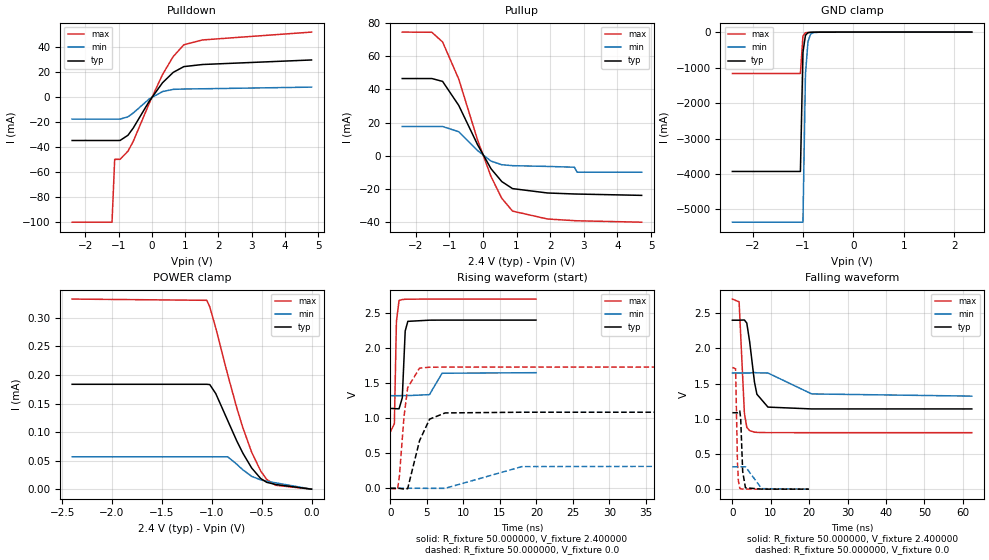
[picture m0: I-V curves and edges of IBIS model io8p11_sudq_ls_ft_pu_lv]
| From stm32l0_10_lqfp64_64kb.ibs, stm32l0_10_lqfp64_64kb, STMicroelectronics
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|   Model io8p11_sudq_ls_ft_pu_lv
[Model]  io8p11_sudq_ls_ft_pu_lv
Model_type I/O
Polarity   Non-Inverting
Enable   Active-Low
Vinl =   0.720000V
Vinh =   1.680000V
Vmeas =  1.200000V
Cref =   50.000000pF
Rref =   100.000000M
Vref =   0.0V
C_comp   2.317700pF   2.286600pF   2.332700pF
[Temperature Range]   25.000000   0.105000k   -40.000000
[Pullup Reference]   2.400000V   1.650000V   2.700000V
[Pulldown Reference]   0.0V   0.0V   0.0V
[POWER Clamp Reference]   2.400000V   1.650000V   2.700000V
[GND Clamp Reference]   0.0V   0.0V   0.0V
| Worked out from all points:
|   slope of the pulldown table from 0 to 0.36 V, typ, clamps not added: 28.4 ohm
|   slope of the pullup table from 0 to 0.36 V, typ, clamps not added: 32.2 ohm
|   GND clamp passes 1 mA (typ) near -0.65 V on its own axis
|   rising waveform, R_fixture 50.000000, V_fixture 2.400000: 20-80 % time 278ps typ, 636ps min, 186ps max; typ from 1.14 V to 2.4 V
|   rising waveform, R_fixture 50.000000, V_fixture 0.0: 20-80 % time 1.58ns typ, 3.85ns min, 917ps max; typ from 0.001 V to 1.09 V
|   falling waveform, R_fixture 50.000000, V_fixture 2.400000: 20-80 % time 1.8ns typ, 5.29ns min, 908ps max; typ from 2.4 V to 1.14 V
|   falling waveform, R_fixture 50.000000, V_fixture 0.0: 20-80 % time 464ps typ, 849ps min, 363ps max; typ from 1.09 V to 0.001 V
[Pulldown]
|Voltage   I(typ)   I(min)   I(max)
-2.4V     -34.71mA   -17.62mA   -100mA
-1.2V     -34.71mA   -17.62mA   -100mA
-1.12V    -34.71mA   -17.62mA   -49.77mA
-960mV    -34.71mA   -17.62mA   -49.77mA
-720mV    -30.52mA   -15.81mA   -43.24mA
-560mV    -24.66mA   -12.69mA   -35.31mA
-80mV     -3.3mA     -1.497mA   -4.982mA
320mV     11.47mA    4.39mA     18.08mA
640mV     19.72mA    6.139mA    32.34mA
960mV     24.33mA    6.432mA    41.77mA
1.52V     26.01mA    6.613mA    45.64mA
4.8V      29.64mA    7.944mA    51.92mA
[Pullup]
|Voltage   I(typ)   I(min)   I(max)
-2.4V     46.57mA    17.6mA     74.62mA
-1.52V    46.57mA    17.6mA     74.51mA
-1.2V     44.84mA    17.6mA     68.64mA
-720mV    30.34mA    14.43mA    46.24mA
-160mV    6.617mA    3.074mA    9.467mA
240mV     -7.917mA   -3.299mA   -12.65mA
560mV     -15.67mA   -5.497mA   -25.76mA
880mV     -19.92mA   -6.062mA   -33.51mA
1.92V     -22.56mA   -6.511mA   -38.27mA
2.72V     -23.16mA   -7mA       -39.27mA
2.8V      -23.2mA    -10mA      -39.35mA
4.72V     -24mA      -10mA      -40.2mA
[GND_clamp]
|Voltage   I(typ)   I(min)   I(max)
-2.4V     -3.929A    -5.359A    -1.166A
-1.05V    -3.929A    -5.359A    -1.166A
-1V       -574.5mA   -5.359A    -109.1mA
-950mV    -90.02mA   -1.192A    -18.55mA
-900mV    -18.41mA   -269.7mA   -9.049mA
-850mV    -6.764mA   -63.59mA   -6.579mA
-800mV    -4.027mA   -16.66mA   -4.859mA
-650mV    -1.043mA   -1.218mA   -1.146mA
2.35V     0A         0A         0A
[POWER_clamp]
|Voltage   I(typ)   I(min)   I(max)
-2.4V     183.7uA    56.67uA    333uA
-1.05V    183.7uA    56.67uA    330.8uA
-1.02V    183.2uA    56.67uA    319.3uA
-960mV    167.4uA    56.67uA    282.2uA
-840mV    120.1uA    56.67uA    200.3uA
-750mV    84.75uA    43.78uA    142.9uA
-690mV    63.55uA    34.11uA    108.5uA
-600mV    37.04uA    22.44uA    64.62uA
-510mV    18.73uA    16.34uA    31.91uA
-450mV    12.06uA    14.02uA    17.25uA
-360mV    8.154uA    11.11uA    6.782uA
0V        0A         0A         0A
[Ramp]
| variable   typ   min   max
dV/dt_r  0.65095/1.57423n   0.19036/3.84287n   1.03799/0.91323n
dV/dt_f  0.75624/1.80298n   0.19416/5.27079n   1.13751/0.90631n
R_load = 50.000000
[Rising Waveform]
R_fixture= 50.000000
V_fixture= 2.400000
V_fixture_min= 1.650000
V_fixture_max= 2.700000
|time   V(typ)   V(min)   V(max)
0s        1.14V      1.322V     803.1mV
560.6ps   1.139V     1.322V     921.3mV
840.8ps   1.136V     1.322V     2.38V
1.201ns   1.135V     1.322V     2.68V
1.642ns   1.291V     1.323V     2.693V
2.042ns   2.244V     1.323V     2.697V
2.402ns   2.382V     1.323V     2.698V
5.365ns   2.399V     1.337V     2.7V
7.087ns   2.4V       1.642V     2.7V
19.94ns   2.4V       1.65V      2.7V
[Rising Waveform]
R_fixture= 50.000000
V_fixture= 0.0
V_fixture_min= 0.0
V_fixture_max= 0.0
|time   V(typ)   V(min)   V(max)
0s        877.7uV    1.336mV    741.5uV
1.001ns   989.6uV    1.332mV    -11.31mV
1.251ns   156.8uV    1.329mV    178.8mV
1.877ns   -9.653mV   1.326mV    1.021V
2.377ns   -4.834mV   1.343mV    1.434V
4.004ns   680.3mV    1.416mV    1.715V
5.38ns    987.5mV    -171.1uV   1.728V
7.508ns   1.076V     541.8uV    1.73V
18.02ns   1.086V     310.4mV    1.73V
62.31ns   1.086V     318.6mV    1.73V
[Falling Waveform]
R_fixture= 50.000000
V_fixture= 2.400000
V_fixture_min= 1.650000
V_fixture_max= 2.700000
|time   V(typ)   V(min)   V(max)
0s        2.4V       1.65V      2.7V
1.752ns   2.4V       1.65V      2.66V
3.128ns   2.403V     1.65V      1.081V
3.754ns   2.359V     1.65V      878mV
4.505ns   2.091V     1.65V      830.9mV
5.756ns   1.52V      1.658V     810.2mV
6.381ns   1.349V     1.652V     806.9mV
9.259ns   1.166V     1.65V      803.4mV
20.65ns   1.14V      1.353V     803.1mV
62.31ns   1.14V      1.322V     803.1mV
[Falling Waveform]
R_fixture= 50.000000
V_fixture= 0.0
V_fixture_min= 0.0
V_fixture_max= 0.0
|time   V(typ)   V(min)   V(max)
0s        1.086V     318.6mV    1.73V
840.8ps   1.086V     318.6mV    1.709V
1.321ns   1.085V     318.6mV    394.6mV
1.562ns   1.09V      318.6mV    122mV
1.922ns   1.112V     318.6mV    15.91mV
2.162ns   1.008V     318.6mV    5.315mV
2.683ns   250.5mV    318.4mV    2.596mV
3.403ns   20.49mV    318.5mV    1.769mV
7.648ns   1.255mV    8.018mV    759uV
19.94ns   877.7uV    1.336mV    741.5uV
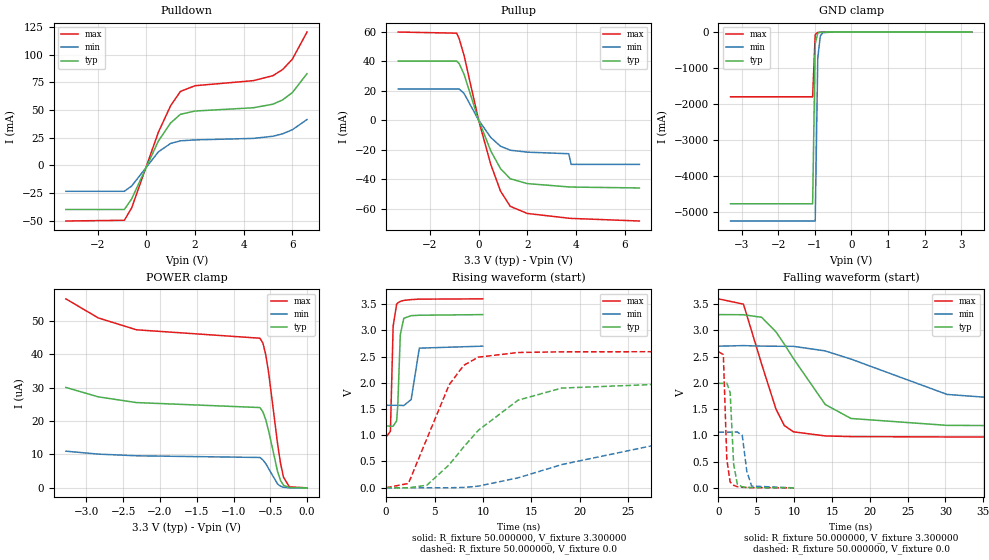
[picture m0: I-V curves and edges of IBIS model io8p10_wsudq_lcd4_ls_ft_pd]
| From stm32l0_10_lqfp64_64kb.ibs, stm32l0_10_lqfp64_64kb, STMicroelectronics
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|   Model io8p10_wsudq_lcd4_ls_ft_pd
[Model]  io8p10_wsudq_lcd4_ls_ft_pd
Model_type I/O
Polarity   Non-Inverting
Enable   Active-Low
Vinl =   0.990000V
Vinh =   2.310000V
Vmeas =  1.650000V
Cref =   50.000000pF
Rref =   100.000000M
Vref =   0.0V
C_comp   3.263700pF   3.224800pF   3.309000pF
[Temperature Range]   25.000000   0.125000k   -40.000000
[Pullup Reference]   3.300000V   2.700000V   3.600000V
[Pulldown Reference]   0.0V   0.0V   0.0V
[POWER Clamp Reference]   3.300000V   2.700000V   3.600000V
[GND Clamp Reference]   0.0V   0.0V   0.0V
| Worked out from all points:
|   slope of the pulldown table from 0 to 0.495 V, typ, clamps not added: 22.6 ohm
|   slope of the pullup table from 0 to 0.495 V, typ, clamps not added: 23.9 ohm
|   GND clamp passes 1 mA (typ) near -0.64 V on its own axis
|   rising waveform, R_fixture 50.000000, V_fixture 3.300000: 20-80 % time 236ps typ, 376ps min, 201ps max; typ from 1.18 V to 3.3 V
|   rising waveform, R_fixture 50.000000, V_fixture 0.0: 20-80 % time 6.53ns typ, 13.6ns min, 3.48ns max; typ from 0 V to 1.99 V
|   falling waveform, R_fixture 50.000000, V_fixture 3.300000: 20-80 % time 5.96ns typ, 12.5ns min, 3.27ns max; typ from 3.3 V to 1.18 V
|   falling waveform, R_fixture 50.000000, V_fixture 0.0: 20-80 % time 413ps typ, 576ps min, 337ps max; typ from 1.99 V to 0 V
[Pulldown]
|Voltage   I(typ)   I(min)   I(max)
-3.3V     -39.83mA   -23.37mA   -50.2mA
-900mV    -39.83mA   -23.37mA   -49.53mA
-600mV    -30.28mA   -18.59mA   -38.45mA
500mV     22.11mA    12.28mA    30.1mA
1V        38.33mA    19.81mA    53.88mA
1.4V      46.1mA     22.18mA    66.72mA
2V        49.07mA    23.02mA    71.93mA
4.4V      52.05mA    24.38mA    76.53mA
5.2V      55.25mA    26.3mA     81.02mA
5.6V      59.18mA    28.57mA    86.57mA
6V        65.79mA    32.24mA    95.97mA
6.6V      82.83mA    41.41mA    120.4mA
[Pullup]
|Voltage   I(typ)   I(min)   I(max)
-3.3V     40.02mA    21.08mA    59.7mA
-900mV    40.02mA    21.08mA    58.93mA
-800mV    38.37mA    21.08mA    55.25mA
-600mV    31.19mA    18.17mA    44.04mA
0V        0A         0A         0A
500mV     -20.88mA   -11.78mA   -30.07mA
900mV     -32.92mA   -17.72mA   -48.15mA
1.3V      -39.75mA   -20.41mA   -58.47mA
2V        -43.05mA   -21.73mA   -63.29mA
3.7V      -45.29mA   -22.8mA    -66.51mA
3.8V      -45.39mA   -30mA      -66.64mA
6.6V      -46mA      -30mA      -68.41mA
[GND_clamp]
|Voltage   I(typ)   I(min)   I(max)
-3.3V     -4.767A    -5.246A    -1.798A
-1.06V    -4.767A    -5.246A    -1.798A
-990mV    -327.3mA   -5.246A    -68.39mA
-920mV    -29.24mA   -722.7mA   -11.25mA
-850mV    -6.784mA   -104.5mA   -6.73mA
-780mV    -3.572mA   -17.39mA   -4.335mA
-500mV    -70.03uA   -187.2uA   -42.37uA
3.28V     73.94uA    88.61uA    51.47uA
[POWER_clamp]
|Voltage   I(typ)   I(min)   I(max)
-3.28V    30.09uA    10.99uA    56.63uA
-2.84V    27.27uA    10.11uA    50.92uA
-2.32V    25.55uA    9.609uA    47.36uA
-640mV    24.06uA    9.1uA      44.84uA
-600mV    22.76uA    8.366uA    43.37uA
-560mV    20.32uA    7.212uA    39.74uA
-520mV    16.86uA    5.676uA    34.15uA
-400mV    4.842uA    1.146uA    13.11uA
-360mV    2.185uA    478.4nA    7.29uA
-320mV    773nA      181.6nA    3.214uA
-240mV    60.58nA    0A         296.5nA
0V        0A         0A         0A
[Ramp]
| variable   typ   min   max
dV/dt_r  1.19406/6.52486n   0.62832/13.55678n   1.55520/3.47452n
dV/dt_f  1.27350/5.95610n   0.65376/12.44267n   1.57835/3.26845n
R_load = 50.000000
[Rising Waveform]
R_fixture= 50.000000
V_fixture= 3.300000
V_fixture_min= 2.700000
V_fixture_max= 3.600000
|time   V(typ)   V(min)   V(max)
0s        1.176V     1.571V     968.8mV
440.4ps   1.175V     1.571V     1.076V
720.7ps   1.172V     1.571V     3.08V
1.081ns   1.274V     1.571V     3.497V
1.201ns   1.566V     1.571V     3.522V
1.461ns   2.92V      1.57V      3.551V
1.822ns   3.229V     1.566V     3.57V
2.583ns   3.279V     1.681V     3.585V
3.423ns   3.287V     2.66V      3.594V
9.97ns    3.299V     2.698V     3.599V
[Rising Waveform]
R_fixture= 50.000000
V_fixture= 0.0
V_fixture_min= 0.0
V_fixture_max= 0.0
|time   V(typ)   V(min)   V(max)
0s        712.4nV    -6.601uV   358.1uV
2.302ns   -2.295mV   -1.631mV   81.19mV
4.204ns   48.28mV    -963.7uV   935.3mV
6.507ns   438mV      -602.5uV   1.963V
8.008ns   777.5mV    5.103mV    2.332V
9.51ns    1.093V     30.17mV    2.488V
13.61ns   1.668V     188.1mV    2.577V
18.12ns   1.899V     440.8mV    2.59V
30.33ns   1.987V     911.5mV    2.592V
49.85ns   1.99V      1.06V      2.592V
[Falling Waveform]
R_fixture= 50.000000
V_fixture= 3.300000
V_fixture_min= 2.700000
V_fixture_max= 3.600000
|time   V(typ)   V(min)   V(max)
0s        3.299V     2.698V     3.599V
3.303ns   3.297V     2.709V     3.498V
5.706ns   3.248V     2.699V     2.356V
7.608ns   2.969V     2.697V     1.497V
8.709ns   2.736V     2.696V     1.186V
9.91ns    2.462V     2.695V     1.067V
14.11ns   1.588V     2.608V     988.8mV
17.52ns   1.321V     2.452V     976.1mV
30.23ns   1.19V      1.779V     969.1mV
49.85ns   1.176V     1.571V     968.8mV
[Falling Waveform]
R_fixture= 50.000000
V_fixture= 0.0
V_fixture_min= 0.0
V_fixture_max= 0.0
|time   V(typ)   V(min)   V(max)
0s        1.99V      1.06V      2.592V
640.6ps   1.99V      1.06V      2.539V
1.101ns   1.996V     1.06V      541.4mV
1.542ns   1.813V     1.06V      108.3mV
2.002ns   453.2mV    1.06V      48.19mV
2.482ns   72.83mV    1.065V     23.05mV
3.143ns   19.01mV    1V         9.776mV
3.744ns   8.62mV     313.6mV    6.748mV
4.384ns   4.909mV    33.16mV    3.76mV
9.97ns    712.4nV    -6.601uV   358.1uV
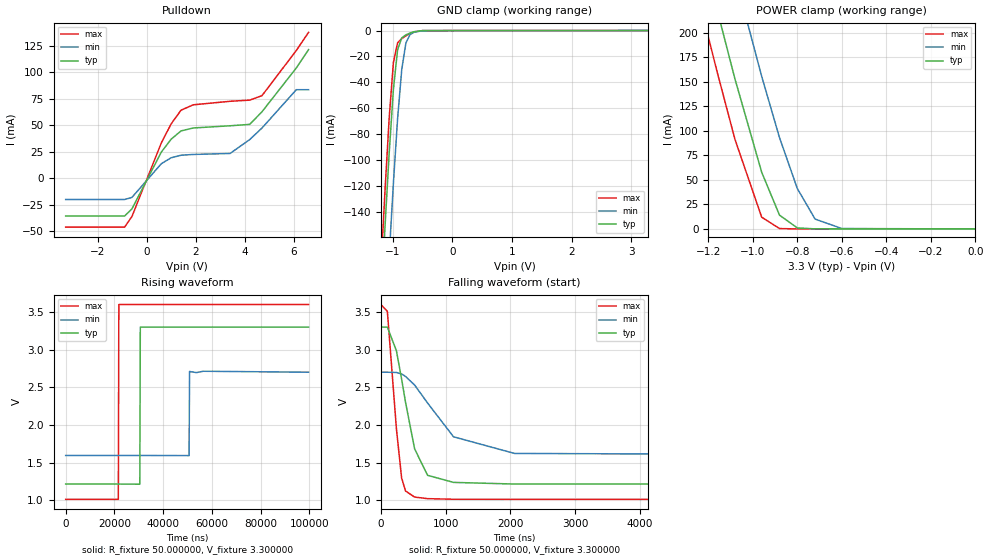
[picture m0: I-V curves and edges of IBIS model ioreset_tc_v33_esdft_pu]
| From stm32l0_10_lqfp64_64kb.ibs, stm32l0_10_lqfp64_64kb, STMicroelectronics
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|   Model ioreset_tc_v33_esdft_pu
[Model]  ioreset_tc_v33_esdft_pu
Model_type I/O_open_drain
Polarity   Inverting
Enable   Active-High
Vinl =   0.990000V
Vinh =   2.310000V
Vmeas =  1.650000V
Cref =   1.0000000000000001E-7F
Rref =   1.000000k
Vref =   3.300000V
C_comp   1.946100pF   1.923200pF   1.977700pF
[Temperature Range]   25.000000   0.125000k   -40.000000
[Pullup Reference]   3.300000V   2.700000V   3.600000V
[Pulldown Reference]   0.0V   0.0V   0.0V
[POWER Clamp Reference]   3.300000V   2.700000V   3.600000V
[GND Clamp Reference]   0.0V   0.0V   0.0V
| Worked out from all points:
|   slope of the pulldown table from 0 to 0.495 V, typ, clamps not added: 23.6 ohm
|   GND clamp passes 1 mA (typ) near -0.65 V on its own axis
|   POWER clamp passes 1 mA (typ) near -0.80 V on its own axis
|   rising waveform, R_fixture 50.000000, V_fixture 3.300000: 20-80 % time 120ns typ, 119ns min, 120ns max; typ from 1.21 V to 3.3 V
|   falling waveform, R_fixture 50.000000, V_fixture 3.300000: 20-80 % time 267ns typ, 617ns min, 142ns max; typ from 3.3 V to 1.21 V
[Pulldown]
|Voltage   I(typ)   I(min)   I(max)
-3.3V     -35.57mA   -19.98mA   -46.06mA
-900mV    -35.57mA   -19.98mA   -46.06mA
-600mV    -28.81mA   -18.01mA   -36.04mA
600mV     24.81mA    13.84mA    33.52mA
1V        36.95mA    19.4mA     51.38mA
1.4V      44.7mA     21.77mA    64.22mA
1.9V      47.49mA    22.51mA    69.34mA
3.4V      49.55mA    23.44mA    72.65mA
4.2V      50.88mA    36.54mA    73.75mA
4.7V      62.75mA    47.4mA     77.96mA
6.1V      104.1mA    83.6mA     120.6mA
6.6V      121.4mA    83.6mA     137.7mA
[GND_clamp]
|Voltage   I(typ)   I(min)   I(max)
-3.3V     -2.25A     -2.322A    -2.233A
-1.2V     -211.8mA   -294.7mA   -184.2mA
-1.13V    -151mA     -233.2mA   -123.1mA
-1.06V    -94.15mA   -173.8mA   -67.07mA
-990mV    -45.49mA   -118mA     -24.73mA
-920mV    -14.87mA   -68.31mA   -9.524mA
-850mV    -5.685mA   -30.05mA   -6.27mA
-780mV    -3.335mA   -9.528mA   -4.082mA
-710mV    -1.932mA   -3.082mA   -2.278mA
-640mV    -914.4uA   -1.28mA    -971uA
-500mV    -57.12uA   -162.8uA   -33.58uA
3.28V     0A         0A         0A
[POWER_clamp]
|Voltage   I(typ)   I(min)   I(max)
-3.28V    2.284A     2.382A     2.228A
-1.28V    332.8mA    439.6mA    269.5mA
-1.24V    295.8mA    402.7mA    232.5mA
-1.2V     259.2mA    365.9mA    195.9mA
-1.16V    223.1mA    329.6mA    160mA
-1.08V    152.8mA    258mA      91.28mA
-960mV    57.81mA    155.5mA    12.03mA
-880mV    14.1mA     93.11mA    413.5uA
-800mV    1.06mA     41.21mA    20.37uA
-720mV    64.72uA    10.03mA    11.63uA
-600mV    14.1uA     431.6uA    9.574uA
0V        0A         0A         0A
[Ramp]
| variable   typ   min   max
dV/dt_r  1.25172/59.96263n   0.66912/60.44991n   1.55334/59.99537n
dV/dt_f  1.25172/0.29030u   0.66354/0.61913u   1.55334/0.15050u
R_load = 50.000000
[Rising Waveform]
R_fixture= 50.000000
V_fixture= 3.300000
V_fixture_min= 2.700000
V_fixture_max= 3.600000
|time   V(typ)   V(min)   V(max)
0s        1.214V     1.594V     1.011V
21.62us   1.214V     1.594V     1.011V
21.82us   1.214V     1.594V     3.6V
30.43us   1.212V     1.594V     3.6V
30.63us   3.3V       1.594V     3.6V
50.65us   3.3V       1.592V     3.6V
50.85us   3.3V       2.71V      3.6V
53.65us   3.3V       2.695V     3.6V
56.46us   3.3V       2.713V     3.6V
99.7us    3.3V       2.7V       3.6V
[Falling Waveform]
R_fixture= 50.000000
V_fixture= 3.300000
V_fixture_min= 2.700000
V_fixture_max= 3.600000
|time   V(typ)   V(min)   V(max)
0s        3.3V       2.7V       3.6V
100.1ns   3.299V     2.7V       3.509V
240.2ns   2.984V     2.697V     1.945V
320.3ns   2.607V     2.677V     1.293V
380.4ns   2.301V     2.644V     1.122V
520.5ns   1.682V     2.53V      1.041V
720.7ns   1.33V      2.291V     1.02V
1.121us   1.236V     1.842V     1.012V
2.062us   1.214V     1.621V     1.011V
9.97us    1.214V     1.594V     1.011V
